One B-rep face of a CAD part: STEP entity #1152.
In plain terms, the planar face has unit normal (1, 0, 0).
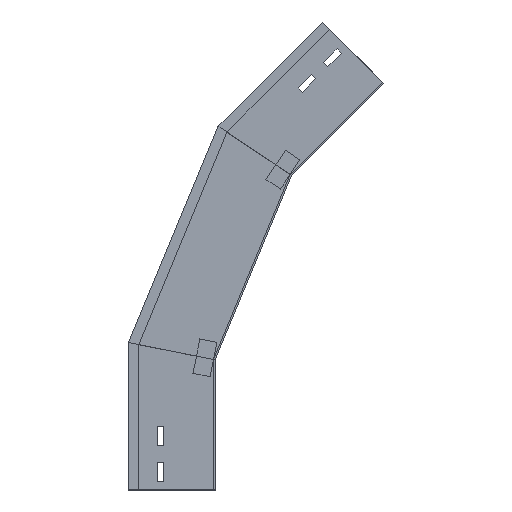
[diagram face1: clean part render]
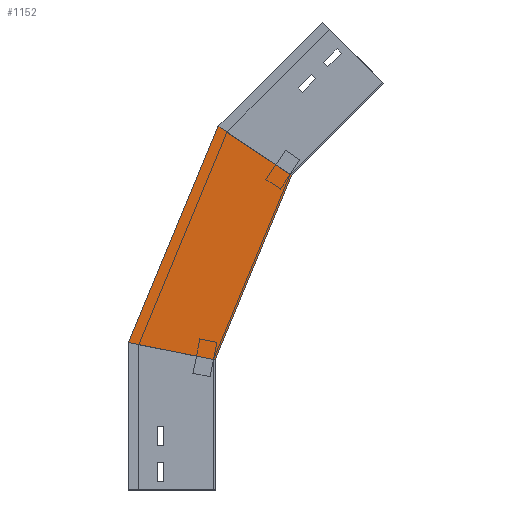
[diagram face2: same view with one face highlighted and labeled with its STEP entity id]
Its self-contained STEP definition (entity closure, numbers rounded to 3 decimals):
#42 = LINE ( 'NONE', #825, #1122 ) ;
#52 = AXIS2_PLACEMENT_3D ( 'NONE', #1051, #1266, #123 ) ;
#60 = VERTEX_POINT ( 'NONE', #531 ) ;
#115 = ORIENTED_EDGE ( 'NONE', *, *, #860, .T. ) ;
#123 = DIRECTION ( 'NONE',  ( 0., 0., -1. ) ) ;
#134 = VECTOR ( 'NONE', #386, 1000. ) ;
#217 = PLANE ( 'NONE',  #52 ) ;
#251 = EDGE_CURVE ( 'NONE', #1182, #60, #1268, .T. ) ;
#331 = DIRECTION ( 'NONE',  ( 0., -0.383, 0.924 ) ) ;
#369 = LINE ( 'NONE', #945, #134 ) ;
#386 = DIRECTION ( 'NONE',  ( 0., -0.383, 0.924 ) ) ;
#426 = CARTESIAN_POINT ( 'NONE',  ( 0., -28.701, 144.291 ) ) ;
#430 = VERTEX_POINT ( 'NONE', #1083 ) ;
#442 = CARTESIAN_POINT ( 'NONE',  ( 0., 8.412, 129.693 ) ) ;
#470 = VECTOR ( 'NONE', #331, 1000. ) ;
#483 = DIRECTION ( 'NONE',  ( 0., -0.831, -0.556 ) ) ;
#531 = CARTESIAN_POINT ( 'NONE',  ( 0., -88.017, 362.492 ) ) ;
#542 = LINE ( 'NONE', #426, #1260 ) ;
#587 = EDGE_CURVE ( 'NONE', #770, #60, #42, .T. ) ;
#735 = ORIENTED_EDGE ( 'NONE', *, *, #587, .T. ) ;
#770 = VERTEX_POINT ( 'NONE', #1027 ) ;
#825 = CARTESIAN_POINT ( 'NONE',  ( 0., -128.891, 335.181 ) ) ;
#860 = EDGE_CURVE ( 'NONE', #430, #770, #369, .T. ) ;
#890 = ORIENTED_EDGE ( 'NONE', *, *, #251, .F. ) ;
#945 = CARTESIAN_POINT ( 'NONE',  ( 0., 100.799, 167.961 ) ) ;
#1027 = CARTESIAN_POINT ( 'NONE',  ( 0., -3.241, 419.138 ) ) ;
#1051 = CARTESIAN_POINT ( 'NONE',  ( 0., 8.412, 129.693 ) ) ;
#1066 = EDGE_CURVE ( 'NONE', #430, #1182, #542, .T. ) ;
#1083 = CARTESIAN_POINT ( 'NONE',  ( 0., 100., 169.891 ) ) ;
#1122 = VECTOR ( 'NONE', #483, 1000. ) ;
#1152 = ADVANCED_FACE ( 'NONE', ( #1390 ), #217, .T. ) ;
#1153 = CARTESIAN_POINT ( 'NONE',  ( 0., 0., 150. ) ) ;
#1182 = VERTEX_POINT ( 'NONE', #1153 ) ;
#1260 = VECTOR ( 'NONE', #1363, 1000. ) ;
#1266 = DIRECTION ( 'NONE',  ( 1., 0., 0. ) ) ;
#1268 = LINE ( 'NONE', #442, #470 ) ;
#1361 = EDGE_LOOP ( 'NONE', ( #115, #735, #890, #1447 ) ) ;
#1363 = DIRECTION ( 'NONE',  ( 0., -0.981, -0.195 ) ) ;
#1390 = FACE_OUTER_BOUND ( 'NONE', #1361, .T. ) ;
#1447 = ORIENTED_EDGE ( 'NONE', *, *, #1066, .F. ) ;
